VERSION 5.7 ;
BUSBITCHARS "[]" ;
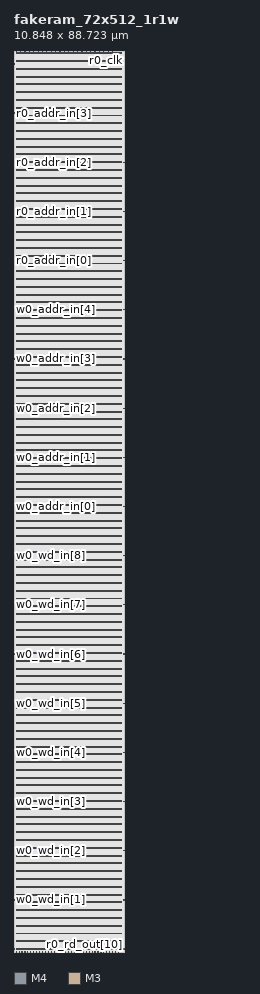
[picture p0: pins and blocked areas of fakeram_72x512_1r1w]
MACRO fakeram_72x512_1r1w
  FOREIGN fakeram_72x512_1r1w 0 0 ;
  SYMMETRY X Y R90 ;
  SIZE 10.848 BY 88.723 ;
  CLASS BLOCK ;
  PIN w0_wd_in[0]
    DIRECTION INPUT ;
    USE SIGNAL ;
    SHAPE ABUTMENT ;
    PORT
      LAYER M4 ;
      RECT 0.000 0.276 0.072 0.300 ;
    END
  END w0_wd_in[0]
  PIN w0_wd_in[1]
    DIRECTION INPUT ;
    USE SIGNAL ;
    SHAPE ABUTMENT ;
    PORT
      LAYER M4 ;
      RECT 0.000 5.124 0.072 5.148 ;
    END
  END w0_wd_in[1]
  PIN w0_wd_in[2]
    DIRECTION INPUT ;
    USE SIGNAL ;
    SHAPE ABUTMENT ;
    PORT
      LAYER M4 ;
      RECT 0.000 9.972 0.072 9.996 ;
    END
  END w0_wd_in[2]
  PIN w0_wd_in[3]
    DIRECTION INPUT ;
    USE SIGNAL ;
    SHAPE ABUTMENT ;
    PORT
      LAYER M4 ;
      RECT 0.000 14.820 0.072 14.844 ;
    END
  END w0_wd_in[3]
  PIN w0_wd_in[4]
    DIRECTION INPUT ;
    USE SIGNAL ;
    SHAPE ABUTMENT ;
    PORT
      LAYER M4 ;
      RECT 0.000 19.668 0.072 19.692 ;
    END
  END w0_wd_in[4]
  PIN w0_wd_in[5]
    DIRECTION INPUT ;
    USE SIGNAL ;
    SHAPE ABUTMENT ;
    PORT
      LAYER M4 ;
      RECT 0.000 24.516 0.072 24.540 ;
    END
  END w0_wd_in[5]
  PIN w0_wd_in[6]
    DIRECTION INPUT ;
    USE SIGNAL ;
    SHAPE ABUTMENT ;
    PORT
      LAYER M4 ;
      RECT 0.000 29.364 0.072 29.388 ;
    END
  END w0_wd_in[6]
  PIN w0_wd_in[7]
    DIRECTION INPUT ;
    USE SIGNAL ;
    SHAPE ABUTMENT ;
    PORT
      LAYER M4 ;
      RECT 0.000 34.212 0.072 34.236 ;
    END
  END w0_wd_in[7]
  PIN w0_wd_in[8]
    DIRECTION INPUT ;
    USE SIGNAL ;
    SHAPE ABUTMENT ;
    PORT
      LAYER M4 ;
      RECT 0.000 39.060 0.072 39.084 ;
    END
  END w0_wd_in[8]
  PIN w0_wd_in[9]
    DIRECTION INPUT ;
    USE SIGNAL ;
    SHAPE ABUTMENT ;
    PORT
      LAYER M4 ;
      RECT 10.776 0.276 10.848 0.300 ;
    END
  END w0_wd_in[9]
  PIN w0_wd_in[10]
    DIRECTION INPUT ;
    USE SIGNAL ;
    SHAPE ABUTMENT ;
    PORT
      LAYER M4 ;
      RECT 10.776 5.124 10.848 5.148 ;
    END
  END w0_wd_in[10]
  PIN w0_wd_in[11]
    DIRECTION INPUT ;
    USE SIGNAL ;
    SHAPE ABUTMENT ;
    PORT
      LAYER M4 ;
      RECT 10.776 9.972 10.848 9.996 ;
    END
  END w0_wd_in[11]
  PIN w0_wd_in[12]
    DIRECTION INPUT ;
    USE SIGNAL ;
    SHAPE ABUTMENT ;
    PORT
      LAYER M4 ;
      RECT 10.776 14.820 10.848 14.844 ;
    END
  END w0_wd_in[12]
  PIN w0_wd_in[13]
    DIRECTION INPUT ;
    USE SIGNAL ;
    SHAPE ABUTMENT ;
    PORT
      LAYER M4 ;
      RECT 10.776 19.668 10.848 19.692 ;
    END
  END w0_wd_in[13]
  PIN w0_wd_in[14]
    DIRECTION INPUT ;
    USE SIGNAL ;
    SHAPE ABUTMENT ;
    PORT
      LAYER M4 ;
      RECT 10.776 24.516 10.848 24.540 ;
    END
  END w0_wd_in[14]
  PIN w0_wd_in[15]
    DIRECTION INPUT ;
    USE SIGNAL ;
    SHAPE ABUTMENT ;
    PORT
      LAYER M4 ;
      RECT 10.776 29.364 10.848 29.388 ;
    END
  END w0_wd_in[15]
  PIN w0_wd_in[16]
    DIRECTION INPUT ;
    USE SIGNAL ;
    SHAPE ABUTMENT ;
    PORT
      LAYER M4 ;
      RECT 10.776 34.212 10.848 34.236 ;
    END
  END w0_wd_in[16]
  PIN w0_wd_in[17]
    DIRECTION INPUT ;
    USE SIGNAL ;
    SHAPE ABUTMENT ;
    PORT
      LAYER M4 ;
      RECT 10.776 39.060 10.848 39.084 ;
    END
  END w0_wd_in[17]
  PIN w0_wd_in[18]
    DIRECTION OUTPUT ;
    USE SIGNAL ;
    SHAPE ABUTMENT ;
    PORT
      LAYER M3 ;
      RECT 0.207 0.000 0.225 0.054 ;
    END
  END w0_wd_in[18]
  PIN w0_wd_in[19]
    DIRECTION OUTPUT ;
    USE SIGNAL ;
    SHAPE ABUTMENT ;
    PORT
      LAYER M3 ;
      RECT 0.495 0.000 0.513 0.054 ;
    END
  END w0_wd_in[19]
  PIN w0_wd_in[20]
    DIRECTION OUTPUT ;
    USE SIGNAL ;
    SHAPE ABUTMENT ;
    PORT
      LAYER M3 ;
      RECT 0.783 0.000 0.801 0.054 ;
    END
  END w0_wd_in[20]
  PIN w0_wd_in[21]
    DIRECTION OUTPUT ;
    USE SIGNAL ;
    SHAPE ABUTMENT ;
    PORT
      LAYER M3 ;
      RECT 1.071 0.000 1.089 0.054 ;
    END
  END w0_wd_in[21]
  PIN w0_wd_in[22]
    DIRECTION OUTPUT ;
    USE SIGNAL ;
    SHAPE ABUTMENT ;
    PORT
      LAYER M3 ;
      RECT 1.359 0.000 1.377 0.054 ;
    END
  END w0_wd_in[22]
  PIN w0_wd_in[23]
    DIRECTION OUTPUT ;
    USE SIGNAL ;
    SHAPE ABUTMENT ;
    PORT
      LAYER M3 ;
      RECT 1.647 0.000 1.665 0.054 ;
    END
  END w0_wd_in[23]
  PIN w0_wd_in[24]
    DIRECTION OUTPUT ;
    USE SIGNAL ;
    SHAPE ABUTMENT ;
    PORT
      LAYER M3 ;
      RECT 1.935 0.000 1.953 0.054 ;
    END
  END w0_wd_in[24]
  PIN w0_wd_in[25]
    DIRECTION OUTPUT ;
    USE SIGNAL ;
    SHAPE ABUTMENT ;
    PORT
      LAYER M3 ;
      RECT 2.223 0.000 2.241 0.054 ;
    END
  END w0_wd_in[25]
  PIN w0_wd_in[26]
    DIRECTION OUTPUT ;
    USE SIGNAL ;
    SHAPE ABUTMENT ;
    PORT
      LAYER M3 ;
      RECT 2.511 0.000 2.529 0.054 ;
    END
  END w0_wd_in[26]
  PIN w0_wd_in[27]
    DIRECTION OUTPUT ;
    USE SIGNAL ;
    SHAPE ABUTMENT ;
    PORT
      LAYER M3 ;
      RECT 2.799 0.000 2.817 0.054 ;
    END
  END w0_wd_in[27]
  PIN w0_wd_in[28]
    DIRECTION OUTPUT ;
    USE SIGNAL ;
    SHAPE ABUTMENT ;
    PORT
      LAYER M3 ;
      RECT 3.087 0.000 3.105 0.054 ;
    END
  END w0_wd_in[28]
  PIN w0_wd_in[29]
    DIRECTION OUTPUT ;
    USE SIGNAL ;
    SHAPE ABUTMENT ;
    PORT
      LAYER M3 ;
      RECT 3.375 0.000 3.393 0.054 ;
    END
  END w0_wd_in[29]
  PIN w0_wd_in[30]
    DIRECTION OUTPUT ;
    USE SIGNAL ;
    SHAPE ABUTMENT ;
    PORT
      LAYER M3 ;
      RECT 3.663 0.000 3.681 0.054 ;
    END
  END w0_wd_in[30]
  PIN w0_wd_in[31]
    DIRECTION OUTPUT ;
    USE SIGNAL ;
    SHAPE ABUTMENT ;
    PORT
      LAYER M3 ;
      RECT 3.951 0.000 3.969 0.054 ;
    END
  END w0_wd_in[31]
  PIN w0_wd_in[32]
    DIRECTION OUTPUT ;
    USE SIGNAL ;
    SHAPE ABUTMENT ;
    PORT
      LAYER M3 ;
      RECT 4.239 0.000 4.257 0.054 ;
    END
  END w0_wd_in[32]
  PIN w0_wd_in[33]
    DIRECTION OUTPUT ;
    USE SIGNAL ;
    SHAPE ABUTMENT ;
    PORT
      LAYER M3 ;
      RECT 4.527 0.000 4.545 0.054 ;
    END
  END w0_wd_in[33]
  PIN w0_wd_in[34]
    DIRECTION OUTPUT ;
    USE SIGNAL ;
    SHAPE ABUTMENT ;
    PORT
      LAYER M3 ;
      RECT 4.815 0.000 4.833 0.054 ;
    END
  END w0_wd_in[34]
  PIN w0_wd_in[35]
    DIRECTION OUTPUT ;
    USE SIGNAL ;
    SHAPE ABUTMENT ;
    PORT
      LAYER M3 ;
      RECT 5.103 0.000 5.121 0.054 ;
    END
  END w0_wd_in[35]
  PIN r0_rd_out[0]
    DIRECTION OUTPUT ;
    USE SIGNAL ;
    SHAPE ABUTMENT ;
    PORT
      LAYER M3 ;
      RECT 5.391 0.000 5.409 0.054 ;
    END
  END r0_rd_out[0]
  PIN r0_rd_out[1]
    DIRECTION OUTPUT ;
    USE SIGNAL ;
    SHAPE ABUTMENT ;
    PORT
      LAYER M3 ;
      RECT 5.679 0.000 5.697 0.054 ;
    END
  END r0_rd_out[1]
  PIN r0_rd_out[2]
    DIRECTION OUTPUT ;
    USE SIGNAL ;
    SHAPE ABUTMENT ;
    PORT
      LAYER M3 ;
      RECT 5.967 0.000 5.985 0.054 ;
    END
  END r0_rd_out[2]
  PIN r0_rd_out[3]
    DIRECTION OUTPUT ;
    USE SIGNAL ;
    SHAPE ABUTMENT ;
    PORT
      LAYER M3 ;
      RECT 6.255 0.000 6.273 0.054 ;
    END
  END r0_rd_out[3]
  PIN r0_rd_out[4]
    DIRECTION OUTPUT ;
    USE SIGNAL ;
    SHAPE ABUTMENT ;
    PORT
      LAYER M3 ;
      RECT 6.543 0.000 6.561 0.054 ;
    END
  END r0_rd_out[4]
  PIN r0_rd_out[5]
    DIRECTION OUTPUT ;
    USE SIGNAL ;
    SHAPE ABUTMENT ;
    PORT
      LAYER M3 ;
      RECT 6.831 0.000 6.849 0.054 ;
    END
  END r0_rd_out[5]
  PIN r0_rd_out[6]
    DIRECTION OUTPUT ;
    USE SIGNAL ;
    SHAPE ABUTMENT ;
    PORT
      LAYER M3 ;
      RECT 7.119 0.000 7.137 0.054 ;
    END
  END r0_rd_out[6]
  PIN r0_rd_out[7]
    DIRECTION OUTPUT ;
    USE SIGNAL ;
    SHAPE ABUTMENT ;
    PORT
      LAYER M3 ;
      RECT 7.407 0.000 7.425 0.054 ;
    END
  END r0_rd_out[7]
  PIN r0_rd_out[8]
    DIRECTION OUTPUT ;
    USE SIGNAL ;
    SHAPE ABUTMENT ;
    PORT
      LAYER M3 ;
      RECT 7.695 0.000 7.713 0.054 ;
    END
  END r0_rd_out[8]
  PIN r0_rd_out[9]
    DIRECTION OUTPUT ;
    USE SIGNAL ;
    SHAPE ABUTMENT ;
    PORT
      LAYER M3 ;
      RECT 7.983 0.000 8.001 0.054 ;
    END
  END r0_rd_out[9]
  PIN r0_rd_out[10]
    DIRECTION OUTPUT ;
    USE SIGNAL ;
    SHAPE ABUTMENT ;
    PORT
      LAYER M3 ;
      RECT 8.271 0.000 8.289 0.054 ;
    END
  END r0_rd_out[10]
  PIN r0_rd_out[11]
    DIRECTION OUTPUT ;
    USE SIGNAL ;
    SHAPE ABUTMENT ;
    PORT
      LAYER M3 ;
      RECT 8.559 0.000 8.577 0.054 ;
    END
  END r0_rd_out[11]
  PIN r0_rd_out[12]
    DIRECTION OUTPUT ;
    USE SIGNAL ;
    SHAPE ABUTMENT ;
    PORT
      LAYER M3 ;
      RECT 8.847 0.000 8.865 0.054 ;
    END
  END r0_rd_out[12]
  PIN r0_rd_out[13]
    DIRECTION OUTPUT ;
    USE SIGNAL ;
    SHAPE ABUTMENT ;
    PORT
      LAYER M3 ;
      RECT 9.135 0.000 9.153 0.054 ;
    END
  END r0_rd_out[13]
  PIN r0_rd_out[14]
    DIRECTION OUTPUT ;
    USE SIGNAL ;
    SHAPE ABUTMENT ;
    PORT
      LAYER M3 ;
      RECT 9.423 0.000 9.441 0.054 ;
    END
  END r0_rd_out[14]
  PIN r0_rd_out[15]
    DIRECTION OUTPUT ;
    USE SIGNAL ;
    SHAPE ABUTMENT ;
    PORT
      LAYER M3 ;
      RECT 9.711 0.000 9.729 0.054 ;
    END
  END r0_rd_out[15]
  PIN r0_rd_out[16]
    DIRECTION OUTPUT ;
    USE SIGNAL ;
    SHAPE ABUTMENT ;
    PORT
      LAYER M3 ;
      RECT 9.999 0.000 10.017 0.054 ;
    END
  END r0_rd_out[16]
  PIN r0_rd_out[17]
    DIRECTION OUTPUT ;
    USE SIGNAL ;
    SHAPE ABUTMENT ;
    PORT
      LAYER M3 ;
      RECT 10.287 0.000 10.305 0.054 ;
    END
  END r0_rd_out[17]
  PIN r0_rd_out[18]
    DIRECTION OUTPUT ;
    USE SIGNAL ;
    SHAPE ABUTMENT ;
    PORT
      LAYER M3 ;
      RECT 0.207 88.669 0.225 88.723 ;
    END
  END r0_rd_out[18]
  PIN r0_rd_out[19]
    DIRECTION OUTPUT ;
    USE SIGNAL ;
    SHAPE ABUTMENT ;
    PORT
      LAYER M3 ;
      RECT 0.639 88.669 0.657 88.723 ;
    END
  END r0_rd_out[19]
  PIN r0_rd_out[20]
    DIRECTION OUTPUT ;
    USE SIGNAL ;
    SHAPE ABUTMENT ;
    PORT
      LAYER M3 ;
      RECT 1.071 88.669 1.089 88.723 ;
    END
  END r0_rd_out[20]
  PIN r0_rd_out[21]
    DIRECTION OUTPUT ;
    USE SIGNAL ;
    SHAPE ABUTMENT ;
    PORT
      LAYER M3 ;
      RECT 1.503 88.669 1.521 88.723 ;
    END
  END r0_rd_out[21]
  PIN r0_rd_out[22]
    DIRECTION OUTPUT ;
    USE SIGNAL ;
    SHAPE ABUTMENT ;
    PORT
      LAYER M3 ;
      RECT 1.935 88.669 1.953 88.723 ;
    END
  END r0_rd_out[22]
  PIN r0_rd_out[23]
    DIRECTION OUTPUT ;
    USE SIGNAL ;
    SHAPE ABUTMENT ;
    PORT
      LAYER M3 ;
      RECT 2.367 88.669 2.385 88.723 ;
    END
  END r0_rd_out[23]
  PIN r0_rd_out[24]
    DIRECTION OUTPUT ;
    USE SIGNAL ;
    SHAPE ABUTMENT ;
    PORT
      LAYER M3 ;
      RECT 2.799 88.669 2.817 88.723 ;
    END
  END r0_rd_out[24]
  PIN r0_rd_out[25]
    DIRECTION OUTPUT ;
    USE SIGNAL ;
    SHAPE ABUTMENT ;
    PORT
      LAYER M3 ;
      RECT 3.231 88.669 3.249 88.723 ;
    END
  END r0_rd_out[25]
  PIN r0_rd_out[26]
    DIRECTION OUTPUT ;
    USE SIGNAL ;
    SHAPE ABUTMENT ;
    PORT
      LAYER M3 ;
      RECT 3.663 88.669 3.681 88.723 ;
    END
  END r0_rd_out[26]
  PIN r0_rd_out[27]
    DIRECTION OUTPUT ;
    USE SIGNAL ;
    SHAPE ABUTMENT ;
    PORT
      LAYER M3 ;
      RECT 4.095 88.669 4.113 88.723 ;
    END
  END r0_rd_out[27]
  PIN r0_rd_out[28]
    DIRECTION OUTPUT ;
    USE SIGNAL ;
    SHAPE ABUTMENT ;
    PORT
      LAYER M3 ;
      RECT 4.527 88.669 4.545 88.723 ;
    END
  END r0_rd_out[28]
  PIN r0_rd_out[29]
    DIRECTION OUTPUT ;
    USE SIGNAL ;
    SHAPE ABUTMENT ;
    PORT
      LAYER M3 ;
      RECT 4.959 88.669 4.977 88.723 ;
    END
  END r0_rd_out[29]
  PIN r0_rd_out[30]
    DIRECTION OUTPUT ;
    USE SIGNAL ;
    SHAPE ABUTMENT ;
    PORT
      LAYER M3 ;
      RECT 5.391 88.669 5.409 88.723 ;
    END
  END r0_rd_out[30]
  PIN r0_rd_out[31]
    DIRECTION OUTPUT ;
    USE SIGNAL ;
    SHAPE ABUTMENT ;
    PORT
      LAYER M3 ;
      RECT 5.823 88.669 5.841 88.723 ;
    END
  END r0_rd_out[31]
  PIN r0_rd_out[32]
    DIRECTION OUTPUT ;
    USE SIGNAL ;
    SHAPE ABUTMENT ;
    PORT
      LAYER M3 ;
      RECT 6.255 88.669 6.273 88.723 ;
    END
  END r0_rd_out[32]
  PIN r0_rd_out[33]
    DIRECTION OUTPUT ;
    USE SIGNAL ;
    SHAPE ABUTMENT ;
    PORT
      LAYER M3 ;
      RECT 6.687 88.669 6.705 88.723 ;
    END
  END r0_rd_out[33]
  PIN r0_rd_out[34]
    DIRECTION OUTPUT ;
    USE SIGNAL ;
    SHAPE ABUTMENT ;
    PORT
      LAYER M3 ;
      RECT 7.119 88.669 7.137 88.723 ;
    END
  END r0_rd_out[34]
  PIN r0_rd_out[35]
    DIRECTION OUTPUT ;
    USE SIGNAL ;
    SHAPE ABUTMENT ;
    PORT
      LAYER M3 ;
      RECT 7.551 88.669 7.569 88.723 ;
    END
  END r0_rd_out[35]
  PIN w0_addr_in[0]
    DIRECTION INPUT ;
    USE SIGNAL ;
    SHAPE ABUTMENT ;
    PORT
      LAYER M4 ;
      RECT 0.000 43.908 0.072 43.932 ;
    END
  END w0_addr_in[0]
  PIN w0_addr_in[1]
    DIRECTION INPUT ;
    USE SIGNAL ;
    SHAPE ABUTMENT ;
    PORT
      LAYER M4 ;
      RECT 0.000 48.756 0.072 48.780 ;
    END
  END w0_addr_in[1]
  PIN w0_addr_in[2]
    DIRECTION INPUT ;
    USE SIGNAL ;
    SHAPE ABUTMENT ;
    PORT
      LAYER M4 ;
      RECT 0.000 53.604 0.072 53.628 ;
    END
  END w0_addr_in[2]
  PIN w0_addr_in[3]
    DIRECTION INPUT ;
    USE SIGNAL ;
    SHAPE ABUTMENT ;
    PORT
      LAYER M4 ;
      RECT 0.000 58.452 0.072 58.476 ;
    END
  END w0_addr_in[3]
  PIN w0_addr_in[4]
    DIRECTION INPUT ;
    USE SIGNAL ;
    SHAPE ABUTMENT ;
    PORT
      LAYER M4 ;
      RECT 0.000 63.300 0.072 63.324 ;
    END
  END w0_addr_in[4]
  PIN w0_addr_in[5]
    DIRECTION INPUT ;
    USE SIGNAL ;
    SHAPE ABUTMENT ;
    PORT
      LAYER M4 ;
      RECT 10.776 43.908 10.848 43.932 ;
    END
  END w0_addr_in[5]
  PIN w0_addr_in[6]
    DIRECTION INPUT ;
    USE SIGNAL ;
    SHAPE ABUTMENT ;
    PORT
      LAYER M4 ;
      RECT 10.776 48.756 10.848 48.780 ;
    END
  END w0_addr_in[6]
  PIN w0_addr_in[7]
    DIRECTION INPUT ;
    USE SIGNAL ;
    SHAPE ABUTMENT ;
    PORT
      LAYER M4 ;
      RECT 10.776 53.604 10.848 53.628 ;
    END
  END w0_addr_in[7]
  PIN w0_addr_in[8]
    DIRECTION INPUT ;
    USE SIGNAL ;
    SHAPE ABUTMENT ;
    PORT
      LAYER M4 ;
      RECT 10.776 58.452 10.848 58.476 ;
    END
  END w0_addr_in[8]
  PIN r0_addr_in[0]
    DIRECTION INPUT ;
    USE SIGNAL ;
    SHAPE ABUTMENT ;
    PORT
      LAYER M4 ;
      RECT 0.000 68.148 0.072 68.172 ;
    END
  END r0_addr_in[0]
  PIN r0_addr_in[1]
    DIRECTION INPUT ;
    USE SIGNAL ;
    SHAPE ABUTMENT ;
    PORT
      LAYER M4 ;
      RECT 0.000 72.996 0.072 73.020 ;
    END
  END r0_addr_in[1]
  PIN r0_addr_in[2]
    DIRECTION INPUT ;
    USE SIGNAL ;
    SHAPE ABUTMENT ;
    PORT
      LAYER M4 ;
      RECT 0.000 77.844 0.072 77.868 ;
    END
  END r0_addr_in[2]
  PIN r0_addr_in[3]
    DIRECTION INPUT ;
    USE SIGNAL ;
    SHAPE ABUTMENT ;
    PORT
      LAYER M4 ;
      RECT 0.000 82.692 0.072 82.716 ;
    END
  END r0_addr_in[3]
  PIN r0_addr_in[4]
    DIRECTION INPUT ;
    USE SIGNAL ;
    SHAPE ABUTMENT ;
    PORT
      LAYER M4 ;
      RECT 0.000 87.540 0.072 87.564 ;
    END
  END r0_addr_in[4]
  PIN r0_addr_in[5]
    DIRECTION INPUT ;
    USE SIGNAL ;
    SHAPE ABUTMENT ;
    PORT
      LAYER M4 ;
      RECT 10.776 63.300 10.848 63.324 ;
    END
  END r0_addr_in[5]
  PIN r0_addr_in[6]
    DIRECTION INPUT ;
    USE SIGNAL ;
    SHAPE ABUTMENT ;
    PORT
      LAYER M4 ;
      RECT 10.776 68.148 10.848 68.172 ;
    END
  END r0_addr_in[6]
  PIN r0_addr_in[7]
    DIRECTION INPUT ;
    USE SIGNAL ;
    SHAPE ABUTMENT ;
    PORT
      LAYER M4 ;
      RECT 10.776 72.996 10.848 73.020 ;
    END
  END r0_addr_in[7]
  PIN r0_addr_in[8]
    DIRECTION INPUT ;
    USE SIGNAL ;
    SHAPE ABUTMENT ;
    PORT
      LAYER M4 ;
      RECT 10.776 77.844 10.848 77.868 ;
    END
  END r0_addr_in[8]
  PIN w0_we_in
    DIRECTION INPUT ;
    USE SIGNAL ;
    SHAPE ABUTMENT ;
    PORT
      LAYER M3 ;
      RECT 7.983 88.669 8.001 88.723 ;
    END
  END w0_we_in
  PIN w0_ce_in
    DIRECTION INPUT ;
    USE SIGNAL ;
    SHAPE ABUTMENT ;
    PORT
      LAYER M3 ;
      RECT 8.415 88.669 8.433 88.723 ;
    END
  END w0_ce_in
  PIN w0_clk
    DIRECTION INPUT ;
    USE SIGNAL ;
    SHAPE ABUTMENT ;
    PORT
      LAYER M3 ;
      RECT 8.847 88.669 8.865 88.723 ;
    END
  END w0_clk
  PIN r0_ce_in
    DIRECTION INPUT ;
    USE SIGNAL ;
    SHAPE ABUTMENT ;
    PORT
      LAYER M3 ;
      RECT 9.279 88.669 9.297 88.723 ;
    END
  END r0_ce_in
  PIN r0_clk
    DIRECTION INPUT ;
    USE SIGNAL ;
    SHAPE ABUTMENT ;
    PORT
      LAYER M3 ;
      RECT 9.711 88.669 9.729 88.723 ;
    END
  END r0_clk
  PIN VSS
    DIRECTION INOUT ;
    USE GROUND ;
    PORT
      LAYER M4 ;
      RECT 0.216 0.240 10.632 0.336 ;
      RECT 0.216 1.008 10.632 1.104 ;
      RECT 0.216 1.776 10.632 1.872 ;
      RECT 0.216 2.544 10.632 2.640 ;
      RECT 0.216 3.312 10.632 3.408 ;
      RECT 0.216 4.080 10.632 4.176 ;
      RECT 0.216 4.848 10.632 4.944 ;
      RECT 0.216 5.616 10.632 5.712 ;
      RECT 0.216 6.384 10.632 6.480 ;
      RECT 0.216 7.152 10.632 7.248 ;
      RECT 0.216 7.920 10.632 8.016 ;
      RECT 0.216 8.688 10.632 8.784 ;
      RECT 0.216 9.456 10.632 9.552 ;
      RECT 0.216 10.224 10.632 10.320 ;
      RECT 0.216 10.992 10.632 11.088 ;
      RECT 0.216 11.760 10.632 11.856 ;
      RECT 0.216 12.528 10.632 12.624 ;
      RECT 0.216 13.296 10.632 13.392 ;
      RECT 0.216 14.064 10.632 14.160 ;
      RECT 0.216 14.832 10.632 14.928 ;
      RECT 0.216 15.600 10.632 15.696 ;
      RECT 0.216 16.368 10.632 16.464 ;
      RECT 0.216 17.136 10.632 17.232 ;
      RECT 0.216 17.904 10.632 18.000 ;
      RECT 0.216 18.672 10.632 18.768 ;
      RECT 0.216 19.440 10.632 19.536 ;
      RECT 0.216 20.208 10.632 20.304 ;
      RECT 0.216 20.976 10.632 21.072 ;
      RECT 0.216 21.744 10.632 21.840 ;
      RECT 0.216 22.512 10.632 22.608 ;
      RECT 0.216 23.280 10.632 23.376 ;
      RECT 0.216 24.048 10.632 24.144 ;
      RECT 0.216 24.816 10.632 24.912 ;
      RECT 0.216 25.584 10.632 25.680 ;
      RECT 0.216 26.352 10.632 26.448 ;
      RECT 0.216 27.120 10.632 27.216 ;
      RECT 0.216 27.888 10.632 27.984 ;
      RECT 0.216 28.656 10.632 28.752 ;
      RECT 0.216 29.424 10.632 29.520 ;
      RECT 0.216 30.192 10.632 30.288 ;
      RECT 0.216 30.960 10.632 31.056 ;
      RECT 0.216 31.728 10.632 31.824 ;
      RECT 0.216 32.496 10.632 32.592 ;
      RECT 0.216 33.264 10.632 33.360 ;
      RECT 0.216 34.032 10.632 34.128 ;
      RECT 0.216 34.800 10.632 34.896 ;
      RECT 0.216 35.568 10.632 35.664 ;
      RECT 0.216 36.336 10.632 36.432 ;
      RECT 0.216 37.104 10.632 37.200 ;
      RECT 0.216 37.872 10.632 37.968 ;
      RECT 0.216 38.640 10.632 38.736 ;
      RECT 0.216 39.408 10.632 39.504 ;
      RECT 0.216 40.176 10.632 40.272 ;
      RECT 0.216 40.944 10.632 41.040 ;
      RECT 0.216 41.712 10.632 41.808 ;
      RECT 0.216 42.480 10.632 42.576 ;
      RECT 0.216 43.248 10.632 43.344 ;
      RECT 0.216 44.016 10.632 44.112 ;
      RECT 0.216 44.784 10.632 44.880 ;
      RECT 0.216 45.552 10.632 45.648 ;
      RECT 0.216 46.320 10.632 46.416 ;
      RECT 0.216 47.088 10.632 47.184 ;
      RECT 0.216 47.856 10.632 47.952 ;
      RECT 0.216 48.624 10.632 48.720 ;
      RECT 0.216 49.392 10.632 49.488 ;
      RECT 0.216 50.160 10.632 50.256 ;
      RECT 0.216 50.928 10.632 51.024 ;
      RECT 0.216 51.696 10.632 51.792 ;
      RECT 0.216 52.464 10.632 52.560 ;
      RECT 0.216 53.232 10.632 53.328 ;
      RECT 0.216 54.000 10.632 54.096 ;
      RECT 0.216 54.768 10.632 54.864 ;
      RECT 0.216 55.536 10.632 55.632 ;
      RECT 0.216 56.304 10.632 56.400 ;
      RECT 0.216 57.072 10.632 57.168 ;
      RECT 0.216 57.840 10.632 57.936 ;
      RECT 0.216 58.608 10.632 58.704 ;
      RECT 0.216 59.376 10.632 59.472 ;
      RECT 0.216 60.144 10.632 60.240 ;
      RECT 0.216 60.912 10.632 61.008 ;
      RECT 0.216 61.680 10.632 61.776 ;
      RECT 0.216 62.448 10.632 62.544 ;
      RECT 0.216 63.216 10.632 63.312 ;
      RECT 0.216 63.984 10.632 64.080 ;
      RECT 0.216 64.752 10.632 64.848 ;
      RECT 0.216 65.520 10.632 65.616 ;
      RECT 0.216 66.288 10.632 66.384 ;
      RECT 0.216 67.056 10.632 67.152 ;
      RECT 0.216 67.824 10.632 67.920 ;
      RECT 0.216 68.592 10.632 68.688 ;
      RECT 0.216 69.360 10.632 69.456 ;
      RECT 0.216 70.128 10.632 70.224 ;
      RECT 0.216 70.896 10.632 70.992 ;
      RECT 0.216 71.664 10.632 71.760 ;
      RECT 0.216 72.432 10.632 72.528 ;
      RECT 0.216 73.200 10.632 73.296 ;
      RECT 0.216 73.968 10.632 74.064 ;
      RECT 0.216 74.736 10.632 74.832 ;
      RECT 0.216 75.504 10.632 75.600 ;
      RECT 0.216 76.272 10.632 76.368 ;
      RECT 0.216 77.040 10.632 77.136 ;
      RECT 0.216 77.808 10.632 77.904 ;
      RECT 0.216 78.576 10.632 78.672 ;
      RECT 0.216 79.344 10.632 79.440 ;
      RECT 0.216 80.112 10.632 80.208 ;
      RECT 0.216 80.880 10.632 80.976 ;
      RECT 0.216 81.648 10.632 81.744 ;
      RECT 0.216 82.416 10.632 82.512 ;
      RECT 0.216 83.184 10.632 83.280 ;
      RECT 0.216 83.952 10.632 84.048 ;
      RECT 0.216 84.720 10.632 84.816 ;
      RECT 0.216 85.488 10.632 85.584 ;
      RECT 0.216 86.256 10.632 86.352 ;
      RECT 0.216 87.024 10.632 87.120 ;
      RECT 0.216 87.792 10.632 87.888 ;
      RECT 0.216 88.560 10.632 88.656 ;
    END
  END VSS
  PIN VDD
    DIRECTION INOUT ;
    USE POWER ;
    PORT
      LAYER M4 ;
      RECT 0.216 0.240 10.632 0.336 ;
      RECT 0.216 1.008 10.632 1.104 ;
      RECT 0.216 1.776 10.632 1.872 ;
      RECT 0.216 2.544 10.632 2.640 ;
      RECT 0.216 3.312 10.632 3.408 ;
      RECT 0.216 4.080 10.632 4.176 ;
      RECT 0.216 4.848 10.632 4.944 ;
      RECT 0.216 5.616 10.632 5.712 ;
      RECT 0.216 6.384 10.632 6.480 ;
      RECT 0.216 7.152 10.632 7.248 ;
      RECT 0.216 7.920 10.632 8.016 ;
      RECT 0.216 8.688 10.632 8.784 ;
      RECT 0.216 9.456 10.632 9.552 ;
      RECT 0.216 10.224 10.632 10.320 ;
      RECT 0.216 10.992 10.632 11.088 ;
      RECT 0.216 11.760 10.632 11.856 ;
      RECT 0.216 12.528 10.632 12.624 ;
      RECT 0.216 13.296 10.632 13.392 ;
      RECT 0.216 14.064 10.632 14.160 ;
      RECT 0.216 14.832 10.632 14.928 ;
      RECT 0.216 15.600 10.632 15.696 ;
      RECT 0.216 16.368 10.632 16.464 ;
      RECT 0.216 17.136 10.632 17.232 ;
      RECT 0.216 17.904 10.632 18.000 ;
      RECT 0.216 18.672 10.632 18.768 ;
      RECT 0.216 19.440 10.632 19.536 ;
      RECT 0.216 20.208 10.632 20.304 ;
      RECT 0.216 20.976 10.632 21.072 ;
      RECT 0.216 21.744 10.632 21.840 ;
      RECT 0.216 22.512 10.632 22.608 ;
      RECT 0.216 23.280 10.632 23.376 ;
      RECT 0.216 24.048 10.632 24.144 ;
      RECT 0.216 24.816 10.632 24.912 ;
      RECT 0.216 25.584 10.632 25.680 ;
      RECT 0.216 26.352 10.632 26.448 ;
      RECT 0.216 27.120 10.632 27.216 ;
      RECT 0.216 27.888 10.632 27.984 ;
      RECT 0.216 28.656 10.632 28.752 ;
      RECT 0.216 29.424 10.632 29.520 ;
      RECT 0.216 30.192 10.632 30.288 ;
      RECT 0.216 30.960 10.632 31.056 ;
      RECT 0.216 31.728 10.632 31.824 ;
      RECT 0.216 32.496 10.632 32.592 ;
      RECT 0.216 33.264 10.632 33.360 ;
      RECT 0.216 34.032 10.632 34.128 ;
      RECT 0.216 34.800 10.632 34.896 ;
      RECT 0.216 35.568 10.632 35.664 ;
      RECT 0.216 36.336 10.632 36.432 ;
      RECT 0.216 37.104 10.632 37.200 ;
      RECT 0.216 37.872 10.632 37.968 ;
      RECT 0.216 38.640 10.632 38.736 ;
      RECT 0.216 39.408 10.632 39.504 ;
      RECT 0.216 40.176 10.632 40.272 ;
      RECT 0.216 40.944 10.632 41.040 ;
      RECT 0.216 41.712 10.632 41.808 ;
      RECT 0.216 42.480 10.632 42.576 ;
      RECT 0.216 43.248 10.632 43.344 ;
      RECT 0.216 44.016 10.632 44.112 ;
      RECT 0.216 44.784 10.632 44.880 ;
      RECT 0.216 45.552 10.632 45.648 ;
      RECT 0.216 46.320 10.632 46.416 ;
      RECT 0.216 47.088 10.632 47.184 ;
      RECT 0.216 47.856 10.632 47.952 ;
      RECT 0.216 48.624 10.632 48.720 ;
      RECT 0.216 49.392 10.632 49.488 ;
      RECT 0.216 50.160 10.632 50.256 ;
      RECT 0.216 50.928 10.632 51.024 ;
      RECT 0.216 51.696 10.632 51.792 ;
      RECT 0.216 52.464 10.632 52.560 ;
      RECT 0.216 53.232 10.632 53.328 ;
      RECT 0.216 54.000 10.632 54.096 ;
      RECT 0.216 54.768 10.632 54.864 ;
      RECT 0.216 55.536 10.632 55.632 ;
      RECT 0.216 56.304 10.632 56.400 ;
      RECT 0.216 57.072 10.632 57.168 ;
      RECT 0.216 57.840 10.632 57.936 ;
      RECT 0.216 58.608 10.632 58.704 ;
      RECT 0.216 59.376 10.632 59.472 ;
      RECT 0.216 60.144 10.632 60.240 ;
      RECT 0.216 60.912 10.632 61.008 ;
      RECT 0.216 61.680 10.632 61.776 ;
      RECT 0.216 62.448 10.632 62.544 ;
      RECT 0.216 63.216 10.632 63.312 ;
      RECT 0.216 63.984 10.632 64.080 ;
      RECT 0.216 64.752 10.632 64.848 ;
      RECT 0.216 65.520 10.632 65.616 ;
      RECT 0.216 66.288 10.632 66.384 ;
      RECT 0.216 67.056 10.632 67.152 ;
      RECT 0.216 67.824 10.632 67.920 ;
      RECT 0.216 68.592 10.632 68.688 ;
      RECT 0.216 69.360 10.632 69.456 ;
      RECT 0.216 70.128 10.632 70.224 ;
      RECT 0.216 70.896 10.632 70.992 ;
      RECT 0.216 71.664 10.632 71.760 ;
      RECT 0.216 72.432 10.632 72.528 ;
      RECT 0.216 73.200 10.632 73.296 ;
      RECT 0.216 73.968 10.632 74.064 ;
      RECT 0.216 74.736 10.632 74.832 ;
      RECT 0.216 75.504 10.632 75.600 ;
      RECT 0.216 76.272 10.632 76.368 ;
      RECT 0.216 77.040 10.632 77.136 ;
      RECT 0.216 77.808 10.632 77.904 ;
      RECT 0.216 78.576 10.632 78.672 ;
      RECT 0.216 79.344 10.632 79.440 ;
      RECT 0.216 80.112 10.632 80.208 ;
      RECT 0.216 80.880 10.632 80.976 ;
      RECT 0.216 81.648 10.632 81.744 ;
      RECT 0.216 82.416 10.632 82.512 ;
      RECT 0.216 83.184 10.632 83.280 ;
      RECT 0.216 83.952 10.632 84.048 ;
      RECT 0.216 84.720 10.632 84.816 ;
      RECT 0.216 85.488 10.632 85.584 ;
      RECT 0.216 86.256 10.632 86.352 ;
      RECT 0.216 87.024 10.632 87.120 ;
      RECT 0.216 87.792 10.632 87.888 ;
      RECT 0.216 88.560 10.632 88.656 ;
    END
  END VDD
  OBS
    LAYER M1 ;
    RECT 0 0 10.848 88.723 ;
    LAYER M2 ;
    RECT 0 0 10.848 88.723 ;
    LAYER M3 ;
    RECT 0 0 10.848 88.723 ;
    LAYER M4 ;
    RECT 0 0 10.848 88.723 ;
  END
END fakeram_72x512_1r1w

END LIBRARY
